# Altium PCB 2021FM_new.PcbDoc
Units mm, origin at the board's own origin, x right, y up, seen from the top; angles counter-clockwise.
Board outline 100 x 90 mm, 2 copper layers (Top Layer, Bottom Layer); 55 components, 25 nets, 113 pads, 0 vias.
Unrouted connection lines stored in the file: 7.

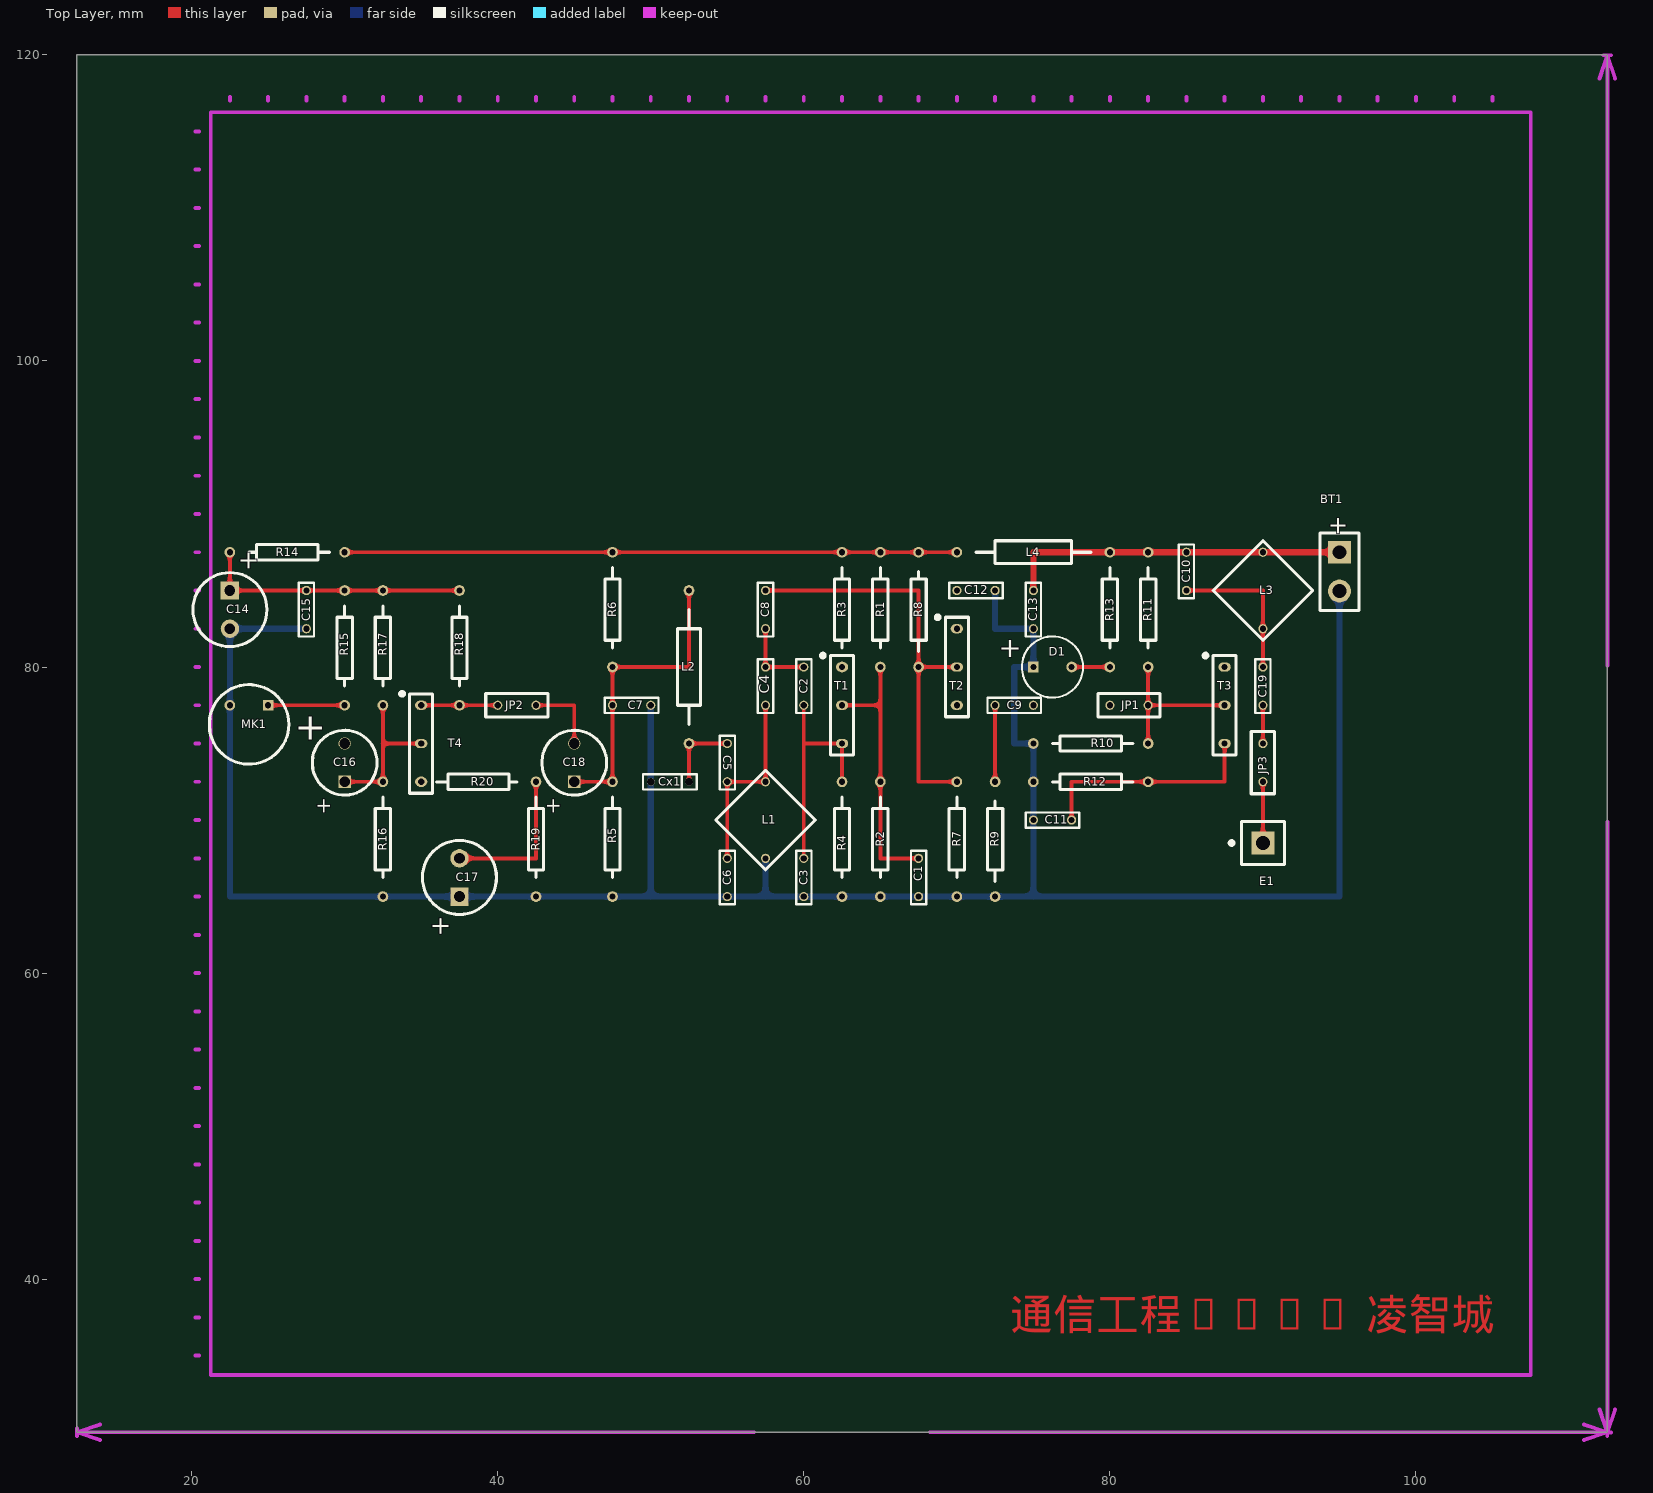
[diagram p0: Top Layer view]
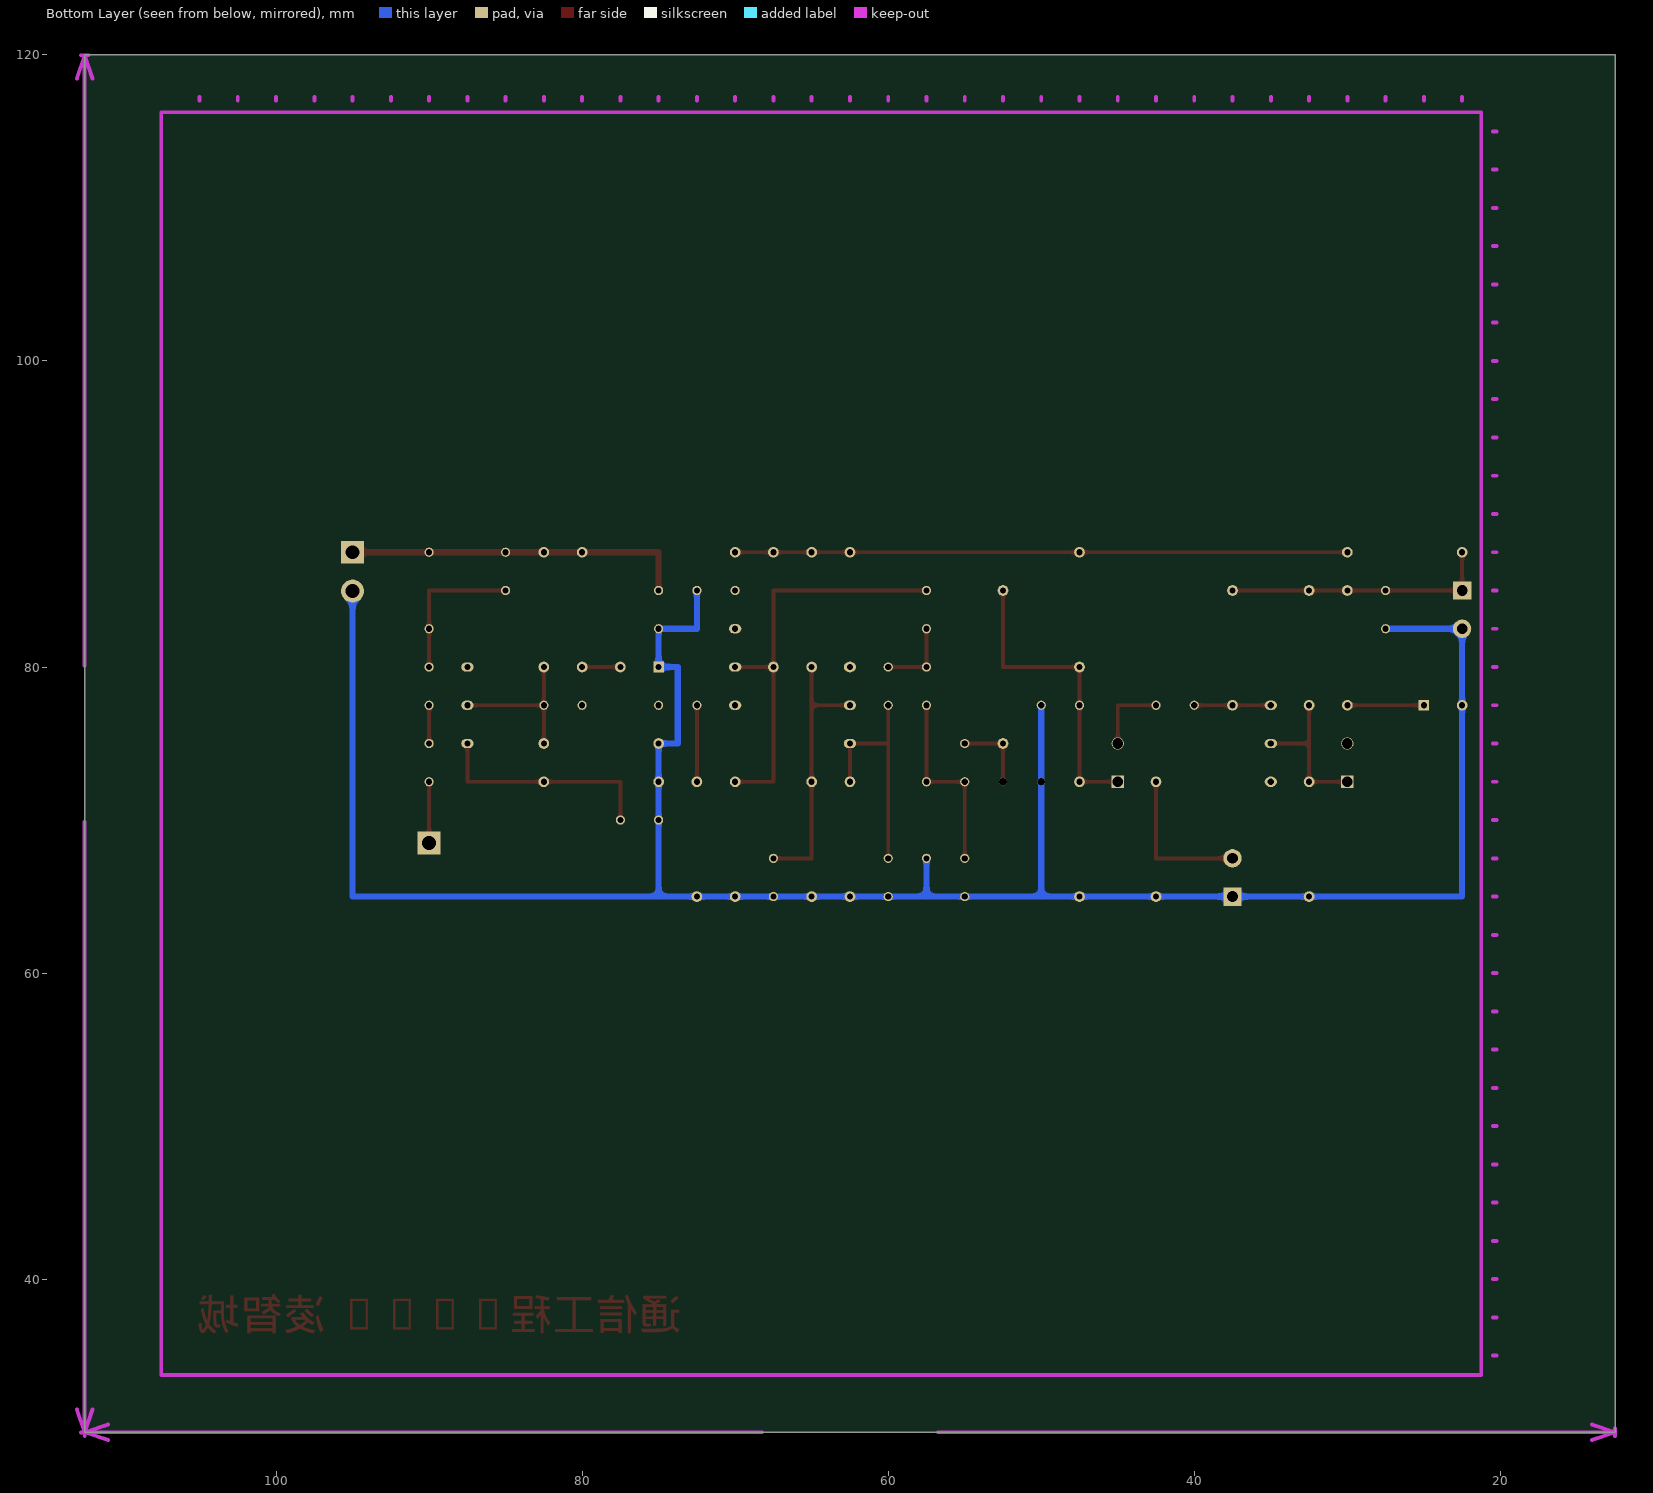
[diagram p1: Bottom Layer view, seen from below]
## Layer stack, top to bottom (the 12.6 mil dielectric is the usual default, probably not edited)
Top Solder: solder mask 0.0102, Solder Resist, Dk 3.5
Top Layer: signal copper 0.0356
Dielectric 1: dielectric 0.32, FR-4, Dk 4.8
Bottom Layer: signal copper 0.0356
Bottom Solder: solder mask 0.0102, Solder Resist, Dk 3.5

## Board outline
12.5,30 112.5,30 112.5,120 12.5,120

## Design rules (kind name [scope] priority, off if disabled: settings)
Clearance [All] p1: gap=0.254 ignorepadtopadclearanceinfootprint=FALSE except(0: Arc-Hole Track-Hole SMDPad-Hole THPad-Hole Via-Hole Fill-Hole Poly-Hole Region-Hole Text-Hole)
PolygonConnect PolygonConnect_1 [All] p1: connectstyle=Relief reliefconductorwidth=0.254 reliefentries=4 polygonreliefangle="90 Angle" airgapwidth=0.254
RoutingVias [All] p1: holewidth=0.711 width=1.27 viastyle="Through Hole" minholewidth=0.711 minwidth=1.27 maxholewidth=0.711 maxwidth=1.27
SolderMaskExpansion [All] p1: expansion=0.102
Width VCC [InNet('NetBT1_1')] p1: maxlimit=0.6 minlimit=0.254 preferedwidth=0.4 minimp=50.000000 maximp=50.000000 favimp=50.000000
Width GND [InNet('GND')] p2: maxlimit=0.6 minlimit=0.254 preferedwidth=0.4 minimp=50.000000 maximp=50.000000 favimp=50.000000
Width [All] p3: maxlimit=0.254 minlimit=0.254 preferedwidth=0.254
30 further rules are at their usual default settings.

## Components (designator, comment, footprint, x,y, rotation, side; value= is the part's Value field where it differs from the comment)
BT1 "Battery" BAT-2 95,86.23 r270 top
C1 "Cap" CAP 67.5,66.25 r90 top value=1000pF
C2 "Cap" CAP 60,78.75 r90 top value=56pF
C3 "Cap" CAP 60,66.25 r90 top value=100pF
C4 "Cap" CAP 57.5,78.75 r270 top value=27pF
C5 "Cap" CAP 55,73.75 r270 top value=10pF
C6 "Cap" CAP 55,66.25 r90 top value=43pF
C7 "Cap" CAP 48.75,77.5 r180 top value=1000pF
C8 "Cap" CAP 57.5,83.75 r270 top value=10pF
C9 "Cap" CAP 73.75,77.5 r180 top value=1000pF
C10 "Cap" CAP 85,86.25 r90 top value=68pF
C11 "Cap" CAP 76.25,70 r0 top value=1000pF
C12 "Cap" CAP 71.25,85 r180 top value=0.01μF
C13 "Cap" CAP 75,83.75 r90 top value=0.01μF
C14 "Cap Pol2" "CAP POL 100μF" 22.5,83.75 r90 top value=100μF
C15 "Cap" CAP 27.5,83.75 r90 top value=0.01μF
C16 "Cap Pol2" "CAP POL 10μF" 30,73.75 r270 top value=10μ
C17 "Cap Pol2" "CAP POL 100μF" 37.5,66.25 r270 top value=100μF
C18 "Cap Pol2" "CAP POL 10μF" 45,73.75 r270 top value=10μF
C19 "Cap" CAP 90,78.75 r90 top value=4.7pF
Cx1 "BB910" "D VACTOR" 51.25,72.5 r0 top
D1 "LED" LED 76.25,80 r180 top
E1 "Antenna" PIN1 90,68.5 r90 top
JP1 "JP" Jumper 81.25,77.5 r0 top
JP2 "JP" Jumper 41.25,77.5 r0 top
JP3 "JP" Jumper 90,73.75 r270 top
L1 "Inductor Adj" ADJ 57.5,70 r180 top value=3.5T,φ3
L2 "Inductor" INDUCTOR 52.5,80 r270 top value=47μH
L3 "Inductor Adj" ADJ 90,85 r180 top value=3.5T,φ3
L4 "Inductor" INDUCTOR 75,87.5 r180 top value=47mH
MK1 "Mic2" Microphone 23.75,76.25 r0 top
R1 "Res2" RES 65,83.75 r90 top value=20K
R2 "Res2" RES 65,68.75 r90 top value=10K
R3 "Res2" RES 62.5,83.75 r90 top value=2K
R4 "Res2" RES 62.5,68.75 r90 top value=2K
R5 "Res2" RES 47.5,68.75 r90 top value=8K
R6 "Res2" RES 47.5,83.75 r90 top value=10K
R7 "Res2" RES 70,68.75 r90 top value=12K
R8 "Res2" RES 67.5,83.75 r270 top value=8K
R9 "Res2" RES 72.5,68.75 r270 top value=1K
R10 "Res2" RES 78.75,75 r0 top value=10K
R11 "Res2" RES 82.5,83.75 r90 top value=20K
R12 "Res2" RES 78.75,72.5 r0 top value=510
R13 "Res2" RES 80,83.75 r90 top value=3.3K
R14 "Res2" RES 26.25,87.5 r0 top value=200
R15 "Res2" RES 30,81.25 r90 top value=4.7K
R16 "Res2" RES 32.5,68.75 r90 top value=10K
R17 "Res2" RES 32.5,81.25 r90 top value=20K
R18 "Res2" RES 37.5,81.25 r90 top value=750
R19 "Res2" RES 42.5,68.75 r90 top value=510
R20 "Res2" RES 38.75,72.5 r180 top value=51
T1 "9018" three 62.5,77.5 r180 top
T2 "9018" three 70,80 r180 top
T3 "9018" three 87.5,77.5 r180 top
T4 "9013" three 35,75 r180 top

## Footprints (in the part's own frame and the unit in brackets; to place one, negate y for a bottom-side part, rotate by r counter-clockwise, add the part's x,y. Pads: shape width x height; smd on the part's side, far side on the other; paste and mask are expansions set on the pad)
ADJ [mm]
  round 0.6 hole 0.4: 1(0,2.5) 2(0,-2.5)
  silkscreen extent -3.25,-3.25 3.25,3.25
BAT-2 [mm] "Battery; 2 Leads"
  rect 1.5x1.5 hole 0.9: 1(-1.27,0)
  round 1.5 hole 0.9: 2(1.27,0)
  silkscreen extent -2.54,-1.27 2.54,1.27
CAP [mm] "Axial Device, Thru-Hole; 2 Leads; 0.4 in Pin Spacing"
  round 0.6 hole 0.4: 1(-1.25,0) 2(1.25,0)
  silkscreen extent -1.75,-0.5 1.75,0.5
"CAP POL 10μF" [mm] "2 Leads"
  round 0.8 hole 0.7: 1(-1.25,0)
  rect 0.8x0.8 hole 0.7: 2(1.25,0)
  silkscreen extent -2.12,-2.12 2.12,2.12
"CAP POL 100μF" [mm] "2 Leads"
  rect 1.2x1.2 hole 0.7: 1(1.25,0)
  round 1.2 hole 0.7: 2(-1.25,0)
  silkscreen extent -2.42,-2.42 2.42,2.42
"D VACTOR" [mm] "Diode, Thru-Hole; 2 Leads; 0.7 in Pin Spacing"
  round 0.5 hole 0.5: 1(1.25,0) 2(-1.25,0)
  silkscreen extent -1.75,-0.5 1.75,0.5
INDUCTOR [mm]
  round 0.7 hole 0.4: 1(-5,0) 2(5,0)
  silkscreen extent -3.75,-0.75 3.75,0.75
Jumper [mm] "Radial Cap, Thru-Hole; 2 Leads; 0.2 in Pin Spacing"
  round 0.6 hole 0.4: 1(-1.25,0) 2(1.25,0)
  silkscreen extent -2.03,-0.76 2.03,0.76
LED [mm] "2 Leads"
  round 0.7 hole 0.4: 1(-1.25,0)
  rect 0.7x0.7 hole 0.4: 2(1.25,0)
  silkscreen extent -2,-2 2,2
Microphone [mm] "2 Leads"
  round 0.7 hole 0.4: 1(-1.25,1.25)
  rect 0.7x0.7 hole 0.4: 2(1.25,1.25)
  silkscreen extent -2.6,-2.6 2.6,2.6
PIN1 [mm] "Generic Antenna; 1 Lead"
  rect 1.5x1.5 hole 0.9: 1(0,0)
  silkscreen extent -1.4,-1.4 1.4,2.17
RES [mm] "Axial Device, Thru-Hole; 2 Leads; 0.4 in Pin Spacing"
  round 0.7 hole 0.4: 1(-3.75,0) 2(3.75,0)
  silkscreen extent -2.5,-0.5 2.75,0.5
three [mm] "TO, Flat Index; 3 In-Line, Axial Leads; Body Dia. 4.8mm; Leads 0.55 x 0.51 mm (max)"
  oval 0.8x0.6 hole 0.4: 1(0,-2.5) 2(0,0) 3(0,2.5)
  silkscreen extent -0.75,-3.37 1.37,3.25

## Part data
BT1: "Multicell Battery"
C1 C2 C3 C4 C5 C6 C7 C8 C9 C10 C11 C12 C13 C15 C19: "Capacitor"
C14 C16 C17 C18: "Polarized Capacitor (Axial)"
Cx1: library part "D Varactor", "Variable Capacitance Diode"
D1: library part LED0, "Typical INFRARED GaAs LED"
E1: "Generic Antenna"
JP1 JP2 JP3: library part SW-PB, "Switch"
L1 L3: "Adjustable Inductor"
MK1: "Microphone"
R1 R2 R3 R4 R5 R6 R7 R8 R9 R10 R11 R12 R13 R14 R15 R16 R17 R18 R19 R20: "Resistor"
T1 T2 T3 T4: library part NPN, "NPN Bipolar Transistor"

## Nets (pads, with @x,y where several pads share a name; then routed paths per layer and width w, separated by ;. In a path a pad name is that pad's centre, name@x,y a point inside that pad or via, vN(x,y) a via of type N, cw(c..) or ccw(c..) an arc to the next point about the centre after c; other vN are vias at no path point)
GND: BT1.2 C1.1 C3.1 C6.1 C7.1 C11.1 C12.1 C13.1 C14.2 C15.1 C17.1 Cx1.2 D1.2 L1.1 MK1.1 R2.1 R4.1 R5.1 R7.1 R9.2 R10.1 R12.1 R16.1 R19.1 | length 155
  Bottom Layer w0.4: C15.1 C14.2 MK1.1 22.5,65 R16.1 C17.1 R19.1 R5.1 50,65 ; C7.1 Cx1.2 50,65 ; L1.1 57.5,65 ; C12.1 72.5,82.5 C13.1 D1.2 73.75,80 73.75,75 R10.1 R12.1 C11.1 75,65 ; BT1.2 95,65 75,65 ; 50,65 C6.1 57.5,65 ; 57.5,65 C3.1 R4.1 R2.1 C1.1 R7.1 R9.2 75,65
NetBT1_1: BT1.1 C10.2 C13.2 L3.2 L4.1 R11.2 R13.2 | length 22.5
  Top Layer w0.4: C13.2 75,87.5 R13.2 R11.2 C10.2 L3.2 BT1.1
NetC1_2: C1.2 R1.1 R2.2 T1.2 | length 17.5
  Top Layer w0.254: T1.2 65,77.5 ; R1.1 65,77.5 ; C1.2 65,67.5 R2.2 65,77.5
NetC2_1: C2.1 C3.2 R4.2 T1.3 | length 15
  Top Layer w0.254: C3.2 60,75 ; C2.1 60,75 ; R4.2 T1.3 60,75
NetC2_2: C2.2 C4.1 C8.2 R3.1 T1.1 | length 5
  Top Layer w0.254: C8.2 C4.1 C2.2
NetC4_2: C4.2 C5.2 C6.2 L1.2 | length 12.5
  Top Layer w0.254: C6.2 C5.2 L1.2 C4.2
NetC5_1: C5.1 Cx1.1 L2.2 | length 5
  Top Layer w0.254: Cx1.1 L2.2 C5.1
NetC7_2: C7.2 C18.2 L2.1 R5.2 R6.1 | length 20
  Top Layer w0.254: C18.2 R5.2 C7.2 R6.1 52.5,80 L2.1
NetC8_1: C8.1 R7.2 R8.2 T2.2 | length 27.5
  Top Layer w0.254: C8.1 67.5,85 R8.2 ; R7.2 67.5,72.5 R8.2 ; T2.2 R8.2
NetC9_1: C9.1 JP1.1
NetC9_2: C9.2 R9.1 T2.3 | length 5
  Top Layer w0.254: R9.1 C9.2
NetC10_1: C10.1 C19.2 L3.1 T3.1 | length 10
  Top Layer w0.254: C10.1 90,85 L3.1 C19.2
NetC11_2: C11.2 R12.2 T3.3 | length 15
  Top Layer w0.254: C11.2 77.5,72.5 R12.2 87.5,72.5 T3.3
NetC12_2: C12.2 L4.2 R1.2 R3.2 R6.2 R8.1 R14.2 T2.1 | length 40
  Top Layer w0.254: R14.2 R6.2 R3.2 R1.2 R8.1 L4.2
NetC14_1: C14.1 C15.2 R14.1 R15.2 R17.2 R18.2 | length 17.5
  Top Layer w0.254: R14.1 C14.1 C15.2 R15.2 R17.2 R18.2
NetC16_1: C16.1 MK1.2 R15.1 | length 5
  Top Layer w0.254: MK1.2 R15.1
NetC16_2: C16.2 R16.2 R17.1 T4.2 | length 10
  Top Layer w0.254: C16.2 R16.2 32.5,75 ; R17.1 32.5,75 ; T4.2 32.5,75
NetC17_2: C17.2 R19.2 R20.1 | length 10
  Top Layer w0.254: C17.2 42.5,67.5 R19.2
NetC18_1: C18.1 JP2.2 | length 5
  Top Layer w0.254: JP2.2 45,77.5 C18.1
NetC19_1: C19.1 JP3.1 | length 2.5
  Top Layer w0.254: JP3.1 C19.1
NetD1_1: D1.1 R13.1 | length 2.5
  Top Layer w0.254: D1.1 R13.1
NetE1_1: E1.1 JP3.2 | length 4
  Top Layer w0.254: E1.1 JP3.2
NetJP1_2: JP1.2 R10.2 R11.1 T3.2 | length 10
  Top Layer w0.254: R10.2 JP1.2 ; R11.1 JP1.2 ; T3.2 JP1.2
NetJP2_1: JP2.1 R18.1 T4.1 | length 5
  Top Layer w0.254: T4.1 R18.1 JP2.1
NetR20_2: R20.2 T4.3

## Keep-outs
Keep-Out Layer:
  lines w0.254: 12.5,29.746 12.5,30.254 ; 14.024,29.492 12.5,30 ; 14.024,30.508 12.5,30 ; 20.25,35 20.5,35 ; 20.25,37.5 20.5,37.5 ; 20.25,40 20.5,40 ; 20.25,42.5 20.5,42.5 ; 20.25,45 20.5,45 ; 20.25,47.5 20.5,47.5 ; 20.25,50 20.5,50 ; 20.25,52.5 20.5,52.5 ; 20.25,55 20.5,55 ; 20.25,57.5 20.5,57.5 ; 20.25,60 20.5,60 ; 20.25,62.5 20.5,62.5 ; 20.25,65 20.5,65 ; 20.25,67.5 20.5,67.5 ; 20.25,70 20.5,70 ; 20.25,72.5 20.5,72.5 ; 20.25,75 20.5,75 ; 20.25,77.5 20.5,77.5 ; 20.25,80 20.5,80 ; 20.25,82.5 20.5,82.5 ; 20.25,85 20.5,85 ; 20.25,87.5 20.5,87.5 ; 20.25,90 20.5,90 ; 20.25,92.5 20.5,92.5 ; 20.25,95 20.5,95 ; 20.25,97.5 20.5,97.5 ; 20.25,100 20.5,100 ; 20.25,102.5 20.5,102.5 ; 20.25,105 20.5,105 ; 20.25,107.5 20.5,107.5 ; 20.25,110 20.5,110 ; 20.25,112.5 20.5,112.5 ; 20.25,115 20.5,115 ; 22.5,117 22.5,117.25 ; 25,117 25,117.25 ; 27.5,117 27.5,117.25 ; 30,117 30,117.25 ; 32.5,117 32.5,117.25 ; 35,117 35,117.25 ; 37.5,117 37.5,117.25 ; 40,117 40,117.25 ; 42.5,117 42.5,117.25 ; 45,117 45,117.25 ; 47.5,117 47.5,117.25 ; 50,117 50,117.25 ; 52.5,117 52.5,117.25 ; 55,117 55,117.25 ; 56.761,30 12.5,30 ; 57.5,117 57.5,117.25 ; 60,117 60,117.25 ; 62.5,117 62.5,117.25 ; 65,117 65,117.25 ; 67.5,117 67.5,117.25 ; 68.239,30 112.5,30 ; 70,117 70,117.25 ; 72.5,117 72.5,117.25 ; 75,117 75,117.25 ; 77.5,117 77.5,117.25 ; 80,117 80,117.25 ; 82.5,117 82.5,117.25 ; 85,117 85,117.25 ; 87.5,117 87.5,117.25 ; 90,117 90,117.25 ; 92.5,117 92.5,117.25 ; 95,117 95,117.25 ; 97.5,117 97.5,117.25 ; 100,117 100,117.25 ; 102.5,117 102.5,117.25 ; 105,117 105,117.25 ; 110.976,29.492 112.5,30 ; 110.976,30.508 112.5,30 ; 112,31.5 112.508,29.976 ; 112,118.452 112.508,119.976 ; 112.254,29.976 112.762,29.976 ; 112.254,119.976 112.762,119.976 ; 112.5,29.746 112.5,30.254 ; 112.508,69.872 112.508,29.976 ; 112.508,80.08 112.508,119.976 ; 113.016,31.5 112.508,29.976 ; 113.016,118.452 112.508,119.976 ; 21.25,33.75 21.25,116.25 107.5,116.25 107.5,33.75 21.25,33.75
  text "01" at 22,117.75 h1.02
  text "02" at 24.25,117.75 h1.02
  text "03" at 26.75,117.75 h1.02
  text "04" at 29.25,117.75 h1.02
  text "05" at 31.75,117.75 h1.02
  text "06" at 34.25,117.75 h1.02
  text "07" at 36.75,117.75 h1.02
  text "08" at 39.25,117.75 h1.02
  text "09" at 41.75,117.75 h1.02
  text "10" at 44.5,117.75 h1.02
  text "11" at 47,117.75 h1.02
  text "12" at 49.5,117.75 h1.02
  text "13" at 52,117.75 h1.02
  text "14" at 54.5,117.75 h1.02
  text "15" at 57,117.75 h1.02
  text "16" at 59.5,117.75 h1.02
  text "17" at 62,117.75 h1.02
  text "18" at 64.5,117.75 h1.02
  text "19" at 67,117.75 h1.02
  text "20" at 69.25,117.75 h1.02
  text "21" at 71.75,117.75 h1.02
  text "22" at 74.25,117.75 h1.02
  text "23" at 76.75,117.75 h1.02
  text "24" at 79.25,117.75 h1.02
  text "25" at 81.75,117.75 h1.02
  text "26" at 84.5,117.75 h1.02
  text "27" at 86.75,117.75 h1.02
  text "28" at 89.25,117.75 h1.02
  text "29" at 91.75,117.75 h1.02
  text "30" at 94.25,117.75 h1.02
  text "31" at 96.75,117.75 h1.02
  text "32" at 99.25,117.75 h1.02
  text "33" at 101.75,117.75 h1.02
  text "34" at 104.25,117.75 h1.02
  text "33" at 18.25,114.5 h1.02
  text "32" at 18.25,112 h1.02
  text "31" at 18.25,109.5 h1.02
  text "30" at 18.25,107 h1.02
  text "29" at 18.25,104.5 h1.02
  text "28" at 18.25,102 h1.02
  text "27" at 18.25,99.5 h1.02
  text "26" at 18.25,97 h1.02
  text "25" at 18.25,94.5 h1.02
  text "24" at 18.25,92 h1.02
  text "23" at 18.25,89.5 h1.02
  text "22" at 18.25,87 h1.02
  text "21" at 18.25,84.5 h1.02
  text "20" at 18.25,82 h1.02
  text "19" at 18.25,79.5 h1.02
  text "18" at 18.25,77 h1.02
  text "17" at 18.25,74.5 h1.02
  text "16" at 18.25,72 h1.02
  text "90 (mm)" at 113.422,70.126 h1.52 r90
  text "15" at 18.25,69.5 h1.02
  text "14" at 18.25,67 h1.02
  text "13" at 18.25,64.5 h1.02
  text "12" at 18.25,62 h1.02
  text "11" at 18.25,59.5 h1.02
  text "10" at 18.25,57 h1.02
  text "09" at 18.25,54.5 h1.02
  text "08" at 18.25,52.25 h1.02
  text "07" at 18.25,49.5 h1.02
  text "06" at 18.25,47 h1.02
  text "05" at 18.25,44.5 h1.02
  text "04" at 18.25,42 h1.02
  text "03" at 18.25,39.5 h1.02
  text "02" at 18.25,37 h1.02
  text "01" at 18.25,34.5 h1.02
  text "100 (mm)" at 57.015,29.086 h1.52

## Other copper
Top Layer:
  text "通信工程1803 凌智城" at 73.5,36 h3.52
